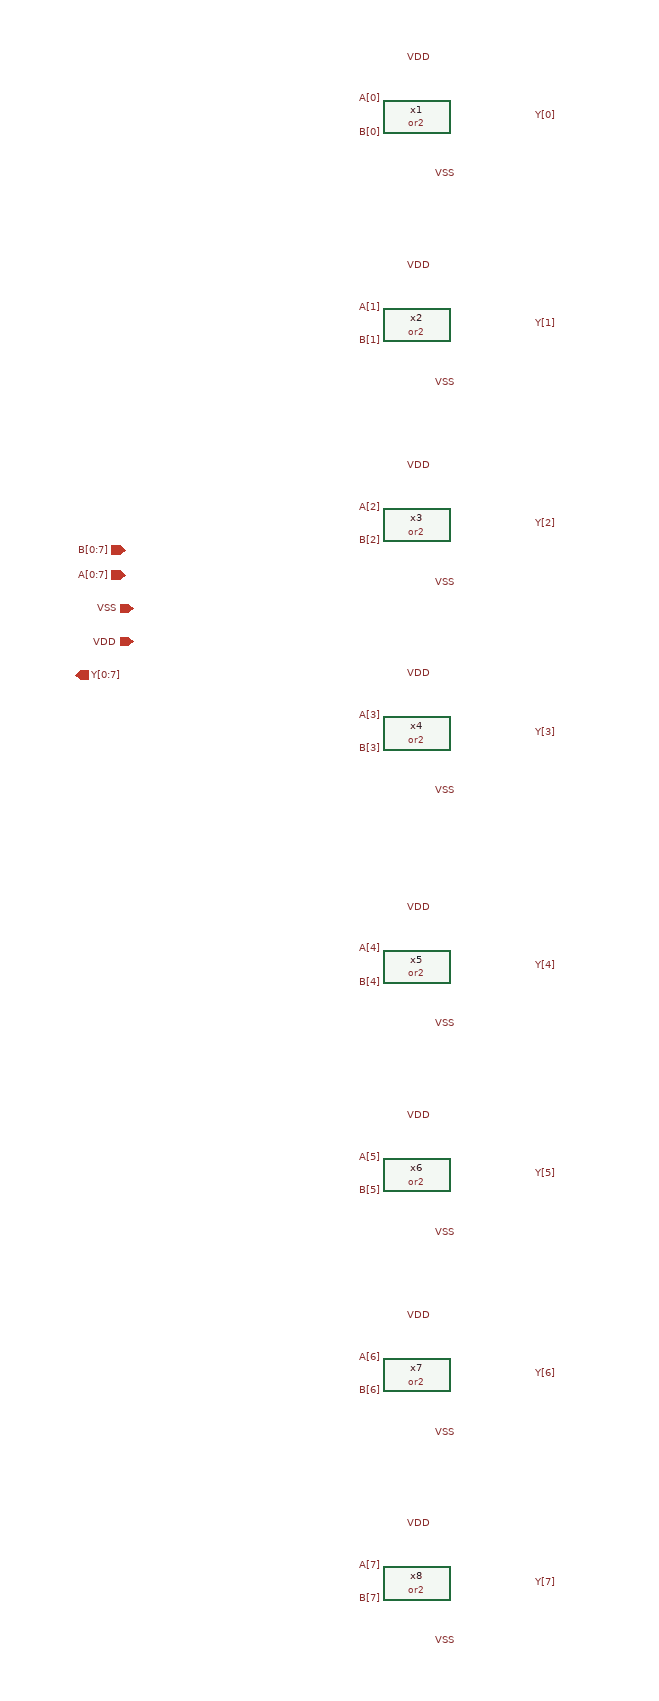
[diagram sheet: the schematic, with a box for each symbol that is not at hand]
v {xschem version=3.1.0 file_version=1.2 }
G {}
K {}
V {}
S {}
E {}
C {devices/ipin.sym} -370 140 0 0 {name=p3 lab=A[0:7]}
C {devices/opin.sym} -430 260 0 0 {name=p9 lab=Y[0:7]}
C {devices/iopin.sym} -360 180 2 0 {name=p6 lab=VSS}
C {devices/iopin.sym} -360 220 2 0 {name=p7 lab=VDD}
C {devices/lab_pin.sym} 0 -480 1 0 {name=l3 sig_type=std_logic lab=VDD}
C {devices/ipin.sym} -370 110 0 0 {name=p1 lab=B[0:7]}
C {devices/lab_pin.sym} -60 -430 0 0 {name=l12 sig_type=std_logic lab=A[0]}
C {devices/lab_pin.sym} -60 -390 0 0 {name=l18 sig_type=std_logic lab=B[0]}
C {devices/lab_pin.sym} 0 -340 2 0 {name=l25 sig_type=std_logic lab=VSS}
C {devices/lab_pin.sym} 120 -410 2 0 {name=l26 sig_type=std_logic lab=Y[0]}
C {or2.sym} -20 -410 0 0 {name=x1}
C {devices/lab_pin.sym} 0 -230 1 0 {name=l1 sig_type=std_logic lab=VDD}
C {devices/lab_pin.sym} -60 -180 0 0 {name=l2 sig_type=std_logic lab=A[1]}
C {devices/lab_pin.sym} -60 -140 0 0 {name=l4 sig_type=std_logic lab=B[1]}
C {devices/lab_pin.sym} 0 -90 2 0 {name=l5 sig_type=std_logic lab=VSS}
C {devices/lab_pin.sym} 120 -160 2 0 {name=l6 sig_type=std_logic lab=Y[1]}
C {or2.sym} -20 -160 0 0 {name=x2}
C {devices/lab_pin.sym} 0 10 1 0 {name=l7 sig_type=std_logic lab=VDD}
C {devices/lab_pin.sym} -60 60 0 0 {name=l8 sig_type=std_logic lab=A[2]}
C {devices/lab_pin.sym} -60 100 0 0 {name=l9 sig_type=std_logic lab=B[2]}
C {devices/lab_pin.sym} 0 150 2 0 {name=l10 sig_type=std_logic lab=VSS}
C {devices/lab_pin.sym} 120 80 2 0 {name=l11 sig_type=std_logic lab=Y[2]}
C {or2.sym} -20 80 0 0 {name=x3}
C {devices/lab_pin.sym} 0 260 1 0 {name=l13 sig_type=std_logic lab=VDD}
C {devices/lab_pin.sym} -60 310 0 0 {name=l14 sig_type=std_logic lab=A[3]}
C {devices/lab_pin.sym} -60 350 0 0 {name=l15 sig_type=std_logic lab=B[3]}
C {devices/lab_pin.sym} 0 400 2 0 {name=l16 sig_type=std_logic lab=VSS}
C {devices/lab_pin.sym} 120 330 2 0 {name=l17 sig_type=std_logic lab=Y[3]}
C {or2.sym} -20 330 0 0 {name=x4}
C {devices/lab_pin.sym} 0 540 1 0 {name=l19 sig_type=std_logic lab=VDD}
C {devices/lab_pin.sym} -60 590 0 0 {name=l20 sig_type=std_logic lab=A[4]}
C {devices/lab_pin.sym} -60 630 0 0 {name=l21 sig_type=std_logic lab=B[4]}
C {devices/lab_pin.sym} 0 680 2 0 {name=l22 sig_type=std_logic lab=VSS}
C {devices/lab_pin.sym} 120 610 2 0 {name=l23 sig_type=std_logic lab=Y[4]}
C {or2.sym} -20 610 0 0 {name=x5}
C {devices/lab_pin.sym} 0 790 1 0 {name=l24 sig_type=std_logic lab=VDD}
C {devices/lab_pin.sym} -60 840 0 0 {name=l27 sig_type=std_logic lab=A[5]}
C {devices/lab_pin.sym} -60 880 0 0 {name=l28 sig_type=std_logic lab=B[5]}
C {devices/lab_pin.sym} 0 930 2 0 {name=l29 sig_type=std_logic lab=VSS}
C {devices/lab_pin.sym} 120 860 2 0 {name=l30 sig_type=std_logic lab=Y[5]}
C {or2.sym} -20 860 0 0 {name=x6}
C {devices/lab_pin.sym} 0 1030 1 0 {name=l31 sig_type=std_logic lab=VDD}
C {devices/lab_pin.sym} -60 1080 0 0 {name=l32 sig_type=std_logic lab=A[6]}
C {devices/lab_pin.sym} -60 1120 0 0 {name=l33 sig_type=std_logic lab=B[6]}
C {devices/lab_pin.sym} 0 1170 2 0 {name=l34 sig_type=std_logic lab=VSS}
C {devices/lab_pin.sym} 120 1100 2 0 {name=l35 sig_type=std_logic lab=Y[6]}
C {or2.sym} -20 1100 0 0 {name=x7}
C {devices/lab_pin.sym} 0 1280 1 0 {name=l36 sig_type=std_logic lab=VDD}
C {devices/lab_pin.sym} -60 1330 0 0 {name=l37 sig_type=std_logic lab=A[7]}
C {devices/lab_pin.sym} -60 1370 0 0 {name=l38 sig_type=std_logic lab=B[7]}
C {devices/lab_pin.sym} 0 1420 2 0 {name=l39 sig_type=std_logic lab=VSS}
C {devices/lab_pin.sym} 120 1350 2 0 {name=l40 sig_type=std_logic lab=Y[7]}
C {or2.sym} -20 1350 0 0 {name=x8}
